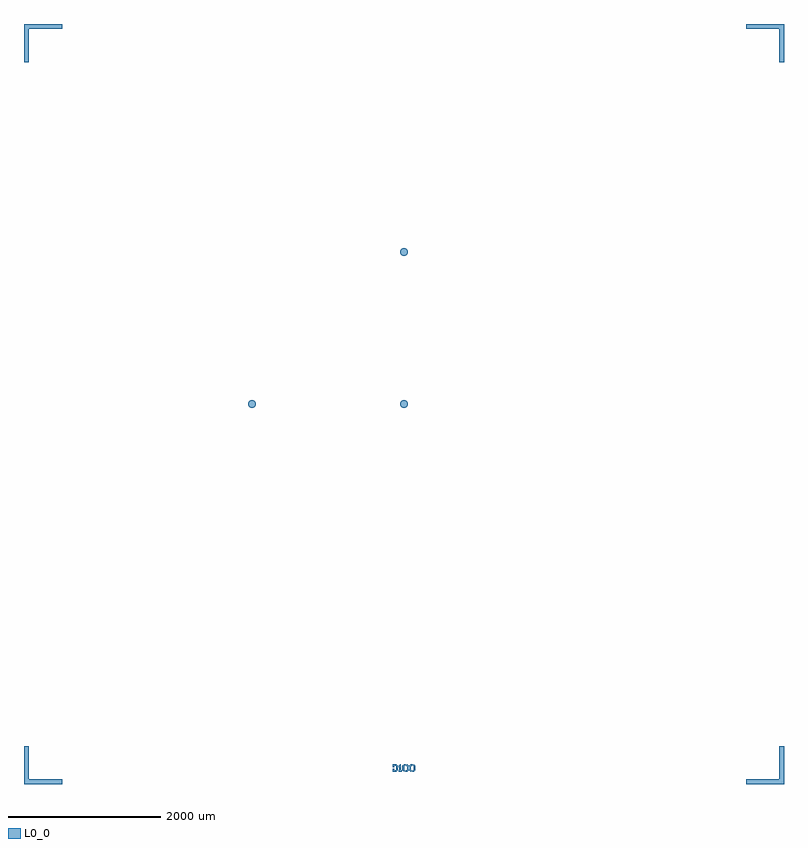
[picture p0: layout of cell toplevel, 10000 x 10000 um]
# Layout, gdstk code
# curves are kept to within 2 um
import gdstk
lib = gdstk.Library(unit=1e-6, precision=1e-09)
def P(c, l, *ps):  # polygons
    for p in ps: c.add(gdstk.Polygon(p, *l))
L0_0 = (0, 0)

circle = lib.new_cell('circle')
P(circle, L0_0, [(50,0),(46.194,19.134),(35.355,35.355),(19.134,46.194),(0,50),(-19.134,46.194),(-35.355,35.355),(-46.194,19.134),(-50,0),(-46.194,-19.134),(-35.355,-35.355),(-19.134,-46.194),(0,-50),(19.134,-46.194),(35.355,-35.355),(46.194,-19.134)])

circle001 = lib.new_cell('circle001')
P(circle001, L0_0, [(-1950,0),(-1953.806,19.134),(-1964.645,35.355),(-1980.866,46.194),(-2000,50),(-2019.134,46.194),(-2035.355,35.355),(-2046.194,19.134),(-2050,0),(-2046.194,-19.134),(-2035.355,-35.355),(-2019.134,-46.194),(-2000,-50),(-1980.866,-46.194),(-1964.645,-35.355),(-1953.806,-19.134)])

circle002 = lib.new_cell('circle002')
P(circle002, L0_0, [(50,2000),(46.194,2019.134),(35.355,2035.355),(19.134,2046.194),(0,2050),(-19.134,2046.194),(-35.355,2035.355),(-46.194,2019.134),(-50,2000),(-46.194,1980.866),(-35.355,1964.645),(-19.134,1953.806),(0,1950),(19.134,1953.806),(35.355,1964.645),(46.194,1980.866)])

text = lib.new_cell('text')
P(text, L0_0, [(10,0),(10,40),(30,40),(30,20),(50,20),(60,30),(60,70),(50,80),(30,80),(30,60),(10,60),(10,100),(60,100),(80,80),(80,20),(60,0)],
  [(100,60),(90,60),(90,80),(110,100),(120,100),(120,20),(130,20),(130,0),(90,0),(90,20),(100,20)],
  [(170,80),(160,70),(160,30),(170,20),(165,0),(160,0),(140,20),(140,80),(160,100),(183,100),(178,80),(170,80)],
  [(190,20),(200,30),(200,70),(190,80),(195,100),(200,100),(220,80),(220,20),(200,0),(177,0),(182,20),(190,20)],
  [(260,80),(250,70),(250,30),(260,20),(255,0),(250,0),(230,20),(230,80),(250,100),(273,100),(268,80),(260,80)],
  [(280,20),(290,30),(290,70),(280,80),(285,100),(290,100),(310,80),(310,20),(290,0),(267,0),(272,20),(280,20)])

die = lib.new_cell('die')
P(die, L0_0, [(5000,5000),(5000,4500),(4940,4500),(4940,4940),(4500,4940),(4500,5000)],
  [(-5000,5000),(-5000,4500),(-4940,4500),(-4940,4940),(-4500,4940),(-4500,5000)],
  [(5000,-5000),(5000,-4500),(4940,-4500),(4940,-4940),(4500,-4940),(4500,-5000)],
  [(-5000,-5000),(-5000,-4500),(-4940,-4500),(-4940,-4940),(-4500,-4940),(-4500,-5000)])
die.add(gdstk.Reference(text, (-160,-4840)))

toplevel = lib.new_cell('toplevel')
toplevel.add(gdstk.Reference(circle, (0,0)))
toplevel.add(gdstk.Reference(circle001, (0,0)))
toplevel.add(gdstk.Reference(circle002, (0,0)))
toplevel.add(gdstk.Reference(die, (0,0)))

lib.write_gds('toplevel.gds')
